VERSION 5.7 ;
  NOWIREEXTENSIONATPIN ON ;
  DIVIDERCHAR "/" ;
  BUSBITCHARS "[]" ;
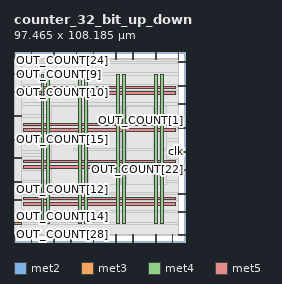
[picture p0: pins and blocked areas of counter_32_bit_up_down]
MACRO counter_32_bit_up_down
  CLASS BLOCK ;
  FOREIGN counter_32_bit_up_down ;
  ORIGIN 0.000 0.000 ;
  SIZE 97.465 BY 108.185 ;
  PIN INP_NEG_RST
    DIRECTION INPUT ;
    USE SIGNAL ;
    ANTENNAGATEAREA 0.126000 ;
    PORT
      LAYER met2 ;
        RECT 22.630 104.185 22.910 108.185 ;
    END
  END INP_NEG_RST
  PIN INP_UP_DOWN
    DIRECTION INPUT ;
    USE SIGNAL ;
    ANTENNAGATEAREA 0.196500 ;
    PORT
      LAYER met2 ;
        RECT 80.590 104.185 80.870 108.185 ;
    END
  END INP_UP_DOWN
  PIN OUT_COUNT[0]
    DIRECTION OUTPUT TRISTATE ;
    USE SIGNAL ;
    ANTENNADIFFAREA 0.795200 ;
    PORT
      LAYER met2 ;
        RECT 0.090 104.185 0.370 108.185 ;
    END
  END OUT_COUNT[0]
  PIN OUT_COUNT[10]
    DIRECTION OUTPUT TRISTATE ;
    USE SIGNAL ;
    ANTENNADIFFAREA 0.795200 ;
    PORT
      LAYER met3 ;
        RECT 0.000 85.040 4.000 85.640 ;
    END
  END OUT_COUNT[10]
  PIN OUT_COUNT[11]
    DIRECTION OUTPUT TRISTATE ;
    USE SIGNAL ;
    ANTENNADIFFAREA 0.795200 ;
    PORT
      LAYER met2 ;
        RECT 80.590 0.000 80.870 4.000 ;
    END
  END OUT_COUNT[11]
  PIN OUT_COUNT[12]
    DIRECTION OUTPUT TRISTATE ;
    USE SIGNAL ;
    ANTENNADIFFAREA 0.795200 ;
    PORT
      LAYER met3 ;
        RECT 0.000 34.040 4.000 34.640 ;
    END
  END OUT_COUNT[12]
  PIN OUT_COUNT[13]
    DIRECTION OUTPUT TRISTATE ;
    USE SIGNAL ;
    ANTENNADIFFAREA 0.795200 ;
    PORT
      LAYER met2 ;
        RECT 67.710 104.185 67.990 108.185 ;
    END
  END OUT_COUNT[13]
  PIN OUT_COUNT[14]
    DIRECTION OUTPUT TRISTATE ;
    USE SIGNAL ;
    ANTENNADIFFAREA 0.795200 ;
    PORT
      LAYER met3 ;
        RECT 0.000 10.240 4.000 10.840 ;
    END
  END OUT_COUNT[14]
  PIN OUT_COUNT[15]
    DIRECTION OUTPUT TRISTATE ;
    USE SIGNAL ;
    ANTENNADIFFAREA 0.795200 ;
    PORT
      LAYER met3 ;
        RECT 0.000 57.840 4.000 58.440 ;
    END
  END OUT_COUNT[15]
  PIN OUT_COUNT[16]
    DIRECTION OUTPUT TRISTATE ;
    USE SIGNAL ;
    ANTENNADIFFAREA 0.795200 ;
    PORT
      LAYER met3 ;
        RECT 93.465 78.240 97.465 78.840 ;
    END
  END OUT_COUNT[16]
  PIN OUT_COUNT[17]
    DIRECTION OUTPUT TRISTATE ;
    USE SIGNAL ;
    ANTENNADIFFAREA 0.795200 ;
    PORT
      LAYER met3 ;
        RECT 93.465 3.440 97.465 4.040 ;
    END
  END OUT_COUNT[17]
  PIN OUT_COUNT[18]
    DIRECTION OUTPUT TRISTATE ;
    USE SIGNAL ;
    ANTENNADIFFAREA 0.795200 ;
    PORT
      LAYER met2 ;
        RECT 90.250 0.000 90.530 4.000 ;
    END
  END OUT_COUNT[18]
  PIN OUT_COUNT[19]
    DIRECTION OUTPUT TRISTATE ;
    USE SIGNAL ;
    ANTENNADIFFAREA 0.795200 ;
    PORT
      LAYER met3 ;
        RECT 0.000 23.840 4.000 24.440 ;
    END
  END OUT_COUNT[19]
  PIN OUT_COUNT[1]
    DIRECTION OUTPUT TRISTATE ;
    USE SIGNAL ;
    ANTENNADIFFAREA 0.795200 ;
    PORT
      LAYER met3 ;
        RECT 93.465 64.640 97.465 65.240 ;
    END
  END OUT_COUNT[1]
  PIN OUT_COUNT[20]
    DIRECTION OUTPUT TRISTATE ;
    USE SIGNAL ;
    ANTENNADIFFAREA 0.795200 ;
    PORT
      LAYER met2 ;
        RECT 0.090 0.000 0.370 4.000 ;
    END
  END OUT_COUNT[20]
  PIN OUT_COUNT[21]
    DIRECTION OUTPUT TRISTATE ;
    USE SIGNAL ;
    ANTENNADIFFAREA 0.795200 ;
    PORT
      LAYER met2 ;
        RECT 58.050 104.185 58.330 108.185 ;
    END
  END OUT_COUNT[21]
  PIN OUT_COUNT[22]
    DIRECTION OUTPUT TRISTATE ;
    USE SIGNAL ;
    ANTENNADIFFAREA 0.795200 ;
    PORT
      LAYER met3 ;
        RECT 93.465 40.840 97.465 41.440 ;
    END
  END OUT_COUNT[22]
  PIN OUT_COUNT[23]
    DIRECTION OUTPUT TRISTATE ;
    USE SIGNAL ;
    ANTENNADIFFAREA 0.795200 ;
    PORT
      LAYER met3 ;
        RECT 0.000 71.440 4.000 72.040 ;
    END
  END OUT_COUNT[23]
  PIN OUT_COUNT[24]
    DIRECTION OUTPUT TRISTATE ;
    USE SIGNAL ;
    ANTENNADIFFAREA 0.795200 ;
    PORT
      LAYER met2 ;
        RECT 9.750 104.185 10.030 108.185 ;
    END
  END OUT_COUNT[24]
  PIN OUT_COUNT[25]
    DIRECTION OUTPUT TRISTATE ;
    USE SIGNAL ;
    ANTENNADIFFAREA 0.795200 ;
    PORT
      LAYER met2 ;
        RECT 67.710 0.000 67.990 4.000 ;
    END
  END OUT_COUNT[25]
  PIN OUT_COUNT[26]
    DIRECTION OUTPUT TRISTATE ;
    USE SIGNAL ;
    ANTENNADIFFAREA 0.795200 ;
    PORT
      LAYER met2 ;
        RECT 93.470 104.185 93.750 108.185 ;
    END
  END OUT_COUNT[26]
  PIN OUT_COUNT[27]
    DIRECTION OUTPUT TRISTATE ;
    USE SIGNAL ;
    ANTENNADIFFAREA 0.795200 ;
    PORT
      LAYER met3 ;
        RECT 93.465 17.040 97.465 17.640 ;
    END
  END OUT_COUNT[27]
  PIN OUT_COUNT[28]
    DIRECTION OUTPUT TRISTATE ;
    USE SIGNAL ;
    ANTENNADIFFAREA 0.795200 ;
    PORT
      LAYER met2 ;
        RECT 9.750 0.000 10.030 4.000 ;
    END
  END OUT_COUNT[28]
  PIN OUT_COUNT[29]
    DIRECTION OUTPUT TRISTATE ;
    USE SIGNAL ;
    ANTENNADIFFAREA 0.795200 ;
    PORT
      LAYER met2 ;
        RECT 22.630 0.000 22.910 4.000 ;
    END
  END OUT_COUNT[29]
  PIN OUT_COUNT[2]
    DIRECTION OUTPUT TRISTATE ;
    USE SIGNAL ;
    ANTENNADIFFAREA 0.795200 ;
    PORT
      LAYER met2 ;
        RECT 32.290 0.000 32.570 4.000 ;
    END
  END OUT_COUNT[2]
  PIN OUT_COUNT[30]
    DIRECTION OUTPUT TRISTATE ;
    USE SIGNAL ;
    ANTENNADIFFAREA 0.795200 ;
    PORT
      LAYER met3 ;
        RECT 93.465 27.240 97.465 27.840 ;
    END
  END OUT_COUNT[30]
  PIN OUT_COUNT[31]
    DIRECTION OUTPUT TRISTATE ;
    USE SIGNAL ;
    ANTENNADIFFAREA 0.795200 ;
    PORT
      LAYER met2 ;
        RECT 45.170 0.000 45.450 4.000 ;
    END
  END OUT_COUNT[31]
  PIN OUT_COUNT[3]
    DIRECTION OUTPUT TRISTATE ;
    USE SIGNAL ;
    ANTENNADIFFAREA 0.795200 ;
    PORT
      LAYER met3 ;
        RECT 93.465 88.440 97.465 89.040 ;
    END
  END OUT_COUNT[3]
  PIN OUT_COUNT[4]
    DIRECTION OUTPUT TRISTATE ;
    USE SIGNAL ;
    ANTENNADIFFAREA 0.795200 ;
    PORT
      LAYER met3 ;
        RECT 93.465 102.040 97.465 102.640 ;
    END
  END OUT_COUNT[4]
  PIN OUT_COUNT[5]
    DIRECTION OUTPUT TRISTATE ;
    USE SIGNAL ;
    ANTENNADIFFAREA 0.795200 ;
    PORT
      LAYER met2 ;
        RECT 35.510 104.185 35.790 108.185 ;
    END
  END OUT_COUNT[5]
  PIN OUT_COUNT[6]
    DIRECTION OUTPUT TRISTATE ;
    USE SIGNAL ;
    ANTENNADIFFAREA 0.795200 ;
    PORT
      LAYER met2 ;
        RECT 45.170 104.185 45.450 108.185 ;
    END
  END OUT_COUNT[6]
  PIN OUT_COUNT[7]
    DIRECTION OUTPUT TRISTATE ;
    USE SIGNAL ;
    ANTENNADIFFAREA 0.795200 ;
    PORT
      LAYER met2 ;
        RECT 58.050 0.000 58.330 4.000 ;
    END
  END OUT_COUNT[7]
  PIN OUT_COUNT[8]
    DIRECTION OUTPUT TRISTATE ;
    USE SIGNAL ;
    ANTENNADIFFAREA 0.795200 ;
    PORT
      LAYER met3 ;
        RECT 0.000 47.640 4.000 48.240 ;
    END
  END OUT_COUNT[8]
  PIN OUT_COUNT[9]
    DIRECTION OUTPUT TRISTATE ;
    USE SIGNAL ;
    ANTENNADIFFAREA 0.795200 ;
    PORT
      LAYER met3 ;
        RECT 0.000 95.240 4.000 95.840 ;
    END
  END OUT_COUNT[9]
  PIN VGND
    DIRECTION INOUT ;
    USE GROUND ;
    PORT
      LAYER met4 ;
        RECT 18.770 10.640 20.370 95.440 ;
    END
    PORT
      LAYER met4 ;
        RECT 40.275 10.640 41.875 95.440 ;
    END
    PORT
      LAYER met4 ;
        RECT 61.780 10.640 63.380 95.440 ;
    END
    PORT
      LAYER met4 ;
        RECT 83.285 10.640 84.885 95.440 ;
    END
    PORT
      LAYER met5 ;
        RECT 5.280 23.920 91.780 25.520 ;
    END
    PORT
      LAYER met5 ;
        RECT 5.280 45.000 91.780 46.600 ;
    END
    PORT
      LAYER met5 ;
        RECT 5.280 66.080 91.780 67.680 ;
    END
    PORT
      LAYER met5 ;
        RECT 5.280 87.160 91.780 88.760 ;
    END
  END VGND
  PIN VPWR
    DIRECTION INOUT ;
    USE POWER ;
    PORT
      LAYER met4 ;
        RECT 15.470 10.640 17.070 95.440 ;
    END
    PORT
      LAYER met4 ;
        RECT 36.975 10.640 38.575 95.440 ;
    END
    PORT
      LAYER met4 ;
        RECT 58.480 10.640 60.080 95.440 ;
    END
    PORT
      LAYER met4 ;
        RECT 79.985 10.640 81.585 95.440 ;
    END
    PORT
      LAYER met5 ;
        RECT 5.280 20.620 91.780 22.220 ;
    END
    PORT
      LAYER met5 ;
        RECT 5.280 41.700 91.780 43.300 ;
    END
    PORT
      LAYER met5 ;
        RECT 5.280 62.780 91.780 64.380 ;
    END
    PORT
      LAYER met5 ;
        RECT 5.280 83.860 91.780 85.460 ;
    END
  END VPWR
  PIN clk
    DIRECTION INPUT ;
    USE SIGNAL ;
    ANTENNAGATEAREA 0.852000 ;
    PORT
      LAYER met3 ;
        RECT 93.465 51.040 97.465 51.640 ;
    END
  END clk
  OBS
      LAYER li1 ;
        RECT 5.520 10.795 91.540 95.285 ;
      LAYER met1 ;
        RECT 0.070 10.640 93.770 95.440 ;
      LAYER met2 ;
        RECT 0.650 103.905 9.470 104.450 ;
        RECT 10.310 103.905 22.350 104.450 ;
        RECT 23.190 103.905 35.230 104.450 ;
        RECT 36.070 103.905 44.890 104.450 ;
        RECT 45.730 103.905 57.770 104.450 ;
        RECT 58.610 103.905 67.430 104.450 ;
        RECT 68.270 103.905 80.310 104.450 ;
        RECT 81.150 103.905 93.190 104.450 ;
        RECT 0.100 4.280 93.740 103.905 ;
        RECT 0.650 3.670 9.470 4.280 ;
        RECT 10.310 3.670 22.350 4.280 ;
        RECT 23.190 3.670 32.010 4.280 ;
        RECT 32.850 3.670 44.890 4.280 ;
        RECT 45.730 3.670 57.770 4.280 ;
        RECT 58.610 3.670 67.430 4.280 ;
        RECT 68.270 3.670 80.310 4.280 ;
        RECT 81.150 3.670 89.970 4.280 ;
        RECT 90.810 3.670 93.740 4.280 ;
      LAYER met3 ;
        RECT 4.000 101.640 93.065 102.505 ;
        RECT 4.000 96.240 93.465 101.640 ;
        RECT 4.400 94.840 93.465 96.240 ;
        RECT 4.000 89.440 93.465 94.840 ;
        RECT 4.000 88.040 93.065 89.440 ;
        RECT 4.000 86.040 93.465 88.040 ;
        RECT 4.400 84.640 93.465 86.040 ;
        RECT 4.000 79.240 93.465 84.640 ;
        RECT 4.000 77.840 93.065 79.240 ;
        RECT 4.000 72.440 93.465 77.840 ;
        RECT 4.400 71.040 93.465 72.440 ;
        RECT 4.000 65.640 93.465 71.040 ;
        RECT 4.000 64.240 93.065 65.640 ;
        RECT 4.000 58.840 93.465 64.240 ;
        RECT 4.400 57.440 93.465 58.840 ;
        RECT 4.000 52.040 93.465 57.440 ;
        RECT 4.000 50.640 93.065 52.040 ;
        RECT 4.000 48.640 93.465 50.640 ;
        RECT 4.400 47.240 93.465 48.640 ;
        RECT 4.000 41.840 93.465 47.240 ;
        RECT 4.000 40.440 93.065 41.840 ;
        RECT 4.000 35.040 93.465 40.440 ;
        RECT 4.400 33.640 93.465 35.040 ;
        RECT 4.000 28.240 93.465 33.640 ;
        RECT 4.000 26.840 93.065 28.240 ;
        RECT 4.000 24.840 93.465 26.840 ;
        RECT 4.400 23.440 93.465 24.840 ;
        RECT 4.000 18.040 93.465 23.440 ;
        RECT 4.000 16.640 93.065 18.040 ;
        RECT 4.000 11.240 93.465 16.640 ;
        RECT 4.400 9.840 93.465 11.240 ;
        RECT 4.000 4.440 93.465 9.840 ;
        RECT 4.000 3.590 93.065 4.440 ;
      LAYER met4 ;
        RECT 21.455 32.815 36.575 77.345 ;
        RECT 38.975 32.815 39.875 77.345 ;
        RECT 42.275 32.815 58.080 77.345 ;
        RECT 60.480 32.815 61.380 77.345 ;
        RECT 63.780 32.815 79.585 77.345 ;
        RECT 81.985 32.815 82.885 77.345 ;
        RECT 85.285 32.815 86.610 77.345 ;
      LAYER met5 ;
        RECT 33.700 51.900 86.820 53.500 ;
  END
END counter_32_bit_up_down
END LIBRARY

